VERSION 5.8 ;
BUSBITCHARS "[]" ;
DIVIDERCHAR "/" ;
CLEARANCEMEASURE EUCLIDEAN ;

SITE coresite
    SIZE 0.0450 BY 0.1440 ;
    CLASS CORE ;
    SYMMETRY Y ;
END coresite

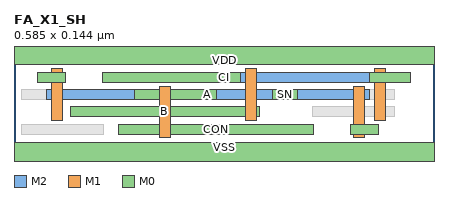
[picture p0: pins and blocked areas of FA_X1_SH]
MACRO FA_X1_SH
  CLASS CORE ;
  ORIGIN 0 0 ;
  FOREIGN FA_X1_SH 0 0 ;
  SIZE 0.5850 BY 0.1440 ;
  SYMMETRY X Y ;
  SITE coresite ;
  PIN A
    DIRECTION INPUT ;
    USE SIGNAL ;
    PORT
      LAYER M2 ;
        RECT 0.0450 0.0910 0.4950 0.0770 ;
      LAYER M1 ;
        RECT 0.2025 0.0960 0.2175 0.0240 ;
        RECT 0.4725 0.0960 0.4875 0.0240 ;
        RECT 0.0525 0.1200 0.0675 0.0480 ;
      LAYER M0 ;
        RECT 0.1680 0.0910 0.2820 0.0770 ;
        RECT 0.4680 0.0430 0.5070 0.0290 ;
        RECT 0.0330 0.1150 0.0720 0.1010 ;
    END
  END A
  PIN B
    DIRECTION INPUT ;
    USE SIGNAL ;
    PORT
      LAYER M2 ;
        RECT 0.3150 0.1150 0.5220 0.1010 ;
      LAYER M1 ;
        RECT 0.3225 0.1200 0.3375 0.0480 ;
        RECT 0.5025 0.1200 0.5175 0.0480 ;
      LAYER M0 ;
        RECT 0.0780 0.0670 0.3420 0.0530 ;
        RECT 0.4950 0.1150 0.5520 0.1010 ;
    END
  END B
  PIN CON
    DIRECTION OUTPUT ;
    USE SIGNAL ;
    PORT
      LAYER M0 ;
        RECT 0.1455 0.0430 0.4170 0.0290 ;
    END
  END CON
  PIN SN
    DIRECTION OUTPUT ;
    USE SIGNAL ;
    PORT
      LAYER M0 ;
        RECT 0.3600 0.0910 0.3945 0.0770 ;
    END
  END SN
  PIN CI
    DIRECTION INPUT ;
    USE SIGNAL ;
    PORT
      LAYER M0 ;
        RECT 0.1230 0.1150 0.4620 0.1010 ;
    END
  END CI
  PIN VSS
    DIRECTION INOUT ;
    USE GROUND ;
    SHAPE ABUTMENT ;
    PORT
      LAYER M0 ;
        RECT 0.0000 -0.0180 0.5850 0.0180 ;
    END
  END VSS
  PIN VDD
    DIRECTION INOUT ;
    USE POWER ;
    SHAPE ABUTMENT ;
    PORT
      LAYER M0 ;
        RECT 0.0000 0.1260 0.5850 0.1620 ;
    END
  END VDD
  OBS
      LAYER V1 ;
        RECT 0.0530 0.0770 0.0670 0.0910 ;
        RECT 0.2030 0.0770 0.2170 0.0910 ;
        RECT 0.4730 0.0770 0.4870 0.0910 ;
        RECT 0.3230 0.1010 0.3370 0.1150 ;
        RECT 0.5030 0.1010 0.5170 0.1150 ;
      LAYER V0 ;
        RECT 0.0530 0.1010 0.0670 0.1150 ;
        RECT 0.2030 0.0770 0.2170 0.0910 ;
        RECT 0.4730 0.0290 0.4870 0.0430 ;
        RECT 0.3230 0.0530 0.3370 0.0670 ;
        RECT 0.5030 0.1010 0.5170 0.1150 ;
      LAYER M0 ;
        RECT 0.0105 0.0290 0.1245 0.0430 ;
        RECT 0.4155 0.0530 0.5295 0.0670 ;
        RECT 0.0105 0.0770 0.1245 0.0910 ;
        RECT 0.4155 0.0770 0.5295 0.0910 ;
  END
END FA_X1_SH

END LIBRARY
